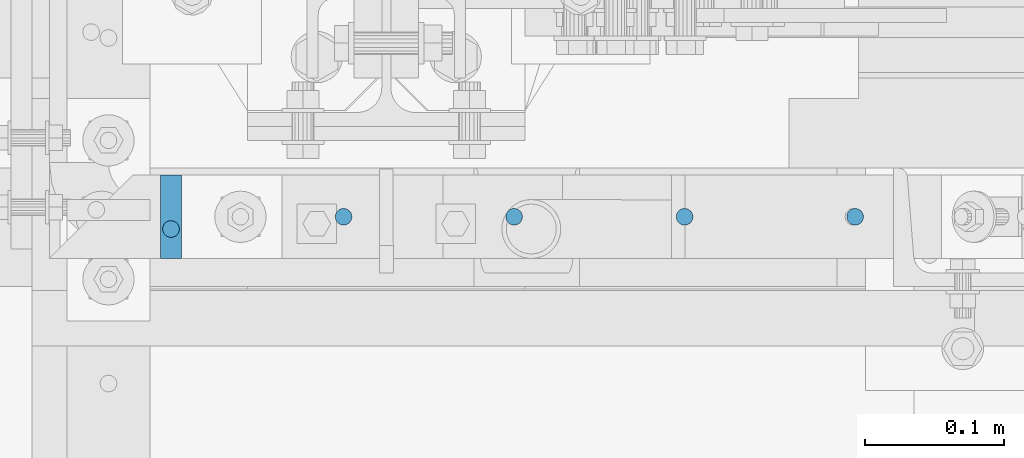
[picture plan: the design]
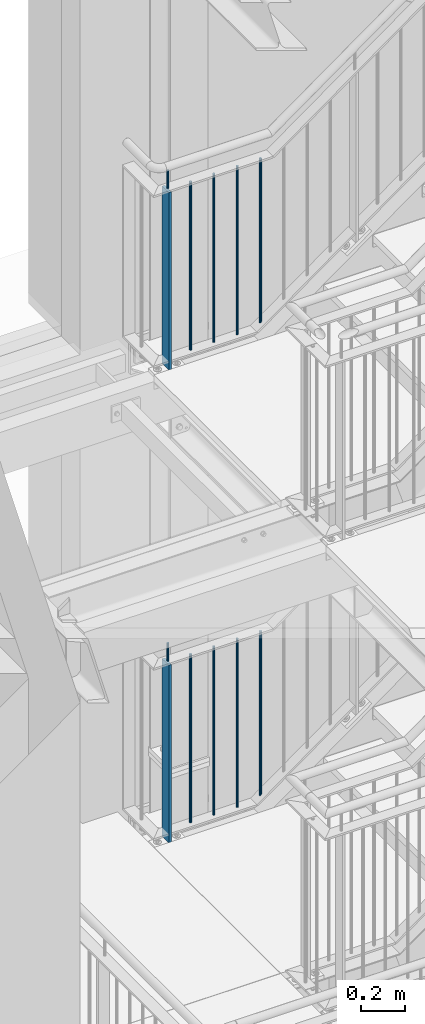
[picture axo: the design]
# One storey, part 70 of 825: 12 columns.
"""IFC2X3 building model written with IfcOpenShell, lengths in millimetres."""

from ifc_helpers import new_model, entity, si_unit, converted_unit, frame, origin, origin_with_axes, origin_2d, place, context, project, spatial, rectangle, circle, extrude, clip, halfspace, material, element, save


model = new_model("IFC2X3")

# Units and contexts
model_context = context("Model", 3, precision=1e-09, world=origin_with_axes())
ifc_project = project(units=[si_unit("LENGTHUNIT", "METRE", prefix="MILLI"), si_unit("AREAUNIT", "SQUARE_METRE"), si_unit("VOLUMEUNIT", "CUBIC_METRE"), converted_unit("PLANEANGLEUNIT", "DEGREE", entity("IfcPlaneAngleMeasure", 0.01745329), si_unit("PLANEANGLEUNIT", "RADIAN"), dimensions=[0, 0, 0, 0, 0, 0, 0])], contexts=[model_context])

# Site, building, storey
site_placement = place(None, origin_with_axes())
site = spatial("IfcSite", under=ifc_project, at=site_placement, CompositionType="ELEMENT")
building_placement = place(site_placement, origin_with_axes())
building = spatial("IfcBuilding", under=site, at=building_placement, Name="1", CompositionType="ELEMENT")
storey_placement = place(building_placement, origin_with_axes())
storey = spatial("IfcBuildingStorey", under=building, at=storey_placement, Name="Default Storey", CompositionType="ELEMENT", Elevation=0.0)

# Columns
ifc_material = material(Name="S235JR")
column_1_placement = place(None, frame((4701.713402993, 7356.736971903, 8359.723292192), z_axis=(0.0, 0.0, 1.0), x_axis=(1.0, 0.0, 0.0)))
element("IfcColumn", 1, at=column_1_placement, inside=storey, material=ifc_material, Name="Railing_Post_Landing#0", ObjectType="Railing_Post_Landing#0", context=model_context, shape_type="Clipping", body=[
    clip(clip(extrude(rectangle(XDim=15.0, YDim=60.0, at=origin_2d()), origin(), (0.0, 0.0, -1.0), 1070.646584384), halfspace(frame((-4701.713402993, -7356.736971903, -1019.722292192), z_axis=(0.0, 0.0, 1.0), x_axis=(1.0, 0.0, 0.0)), True)), halfspace(frame((-4701.713402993, -7356.736971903, -30.924292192), z_axis=(0.0, 0.0, -1.0), x_axis=(-1.0, 0.0, 0.0)), True)),
])
column_2_placement = place(None, frame((4825.963402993, 7356.736971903, 8342.285281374), z_axis=(0.0, 0.0, 1.0), x_axis=(1.0, 0.0, 0.0)))
element("IfcColumn", 2, at=column_2_placement, inside=storey, material=ifc_material, Name="Railing_Picket_Landing#0", ObjectType="Railing_Picket_Landing#0", context=model_context, shape_type="Clipping", body=[
    clip(clip(extrude(circle(Radius=6.0, at=origin_2d()), origin(), (0.0, 0.0, -1.0), 965.770562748), halfspace(frame((-4825.963402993, -7356.736971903, -13.486281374), z_axis=(0.0, 0.0, -1.0), x_axis=(-1.0, 0.0, 0.0)), True)), halfspace(frame((-4825.963402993, -7356.736971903, -952.284281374), z_axis=(0.0, 0.0, 1.0), x_axis=(1.0, 0.0, 0.0)), True)),
])
column_3_placement = place(None, frame((4948.713426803, 7356.736971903, 8342.285281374), z_axis=(0.0, 0.0, 1.0), x_axis=(1.0, 0.0, 0.0)))
element("IfcColumn", 3, at=column_3_placement, inside=storey, material=ifc_material, Name="Railing_Picket_Landing#1", ObjectType="Railing_Picket_Landing#1", context=model_context, shape_type="Clipping", body=[
    clip(clip(extrude(circle(Radius=6.0, at=origin_2d()), origin(), (0.0, 0.0, -1.0), 965.770562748), halfspace(frame((-4948.713426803, -7356.736971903, -13.486281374), z_axis=(0.0, 0.0, -1.0), x_axis=(-1.0, 0.0, 0.0)), True)), halfspace(frame((-4948.713426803, -7356.736971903, -952.284281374), z_axis=(0.0, 0.0, 1.0), x_axis=(1.0, 0.0, 0.0)), True)),
])
column_4_placement = place(None, frame((5071.463450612, 7356.736971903, 8342.285281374), z_axis=(0.0, 0.0, 1.0), x_axis=(1.0, 0.0, 0.0)))
element("IfcColumn", 4, at=column_4_placement, inside=storey, material=ifc_material, Name="Railing_Picket_Landing#2", ObjectType="Railing_Picket_Landing#2", context=model_context, shape_type="Clipping", body=[
    clip(extrude(circle(Radius=6.0, at=origin_2d()), origin(), (0.0, 0.0, -1.0), 952.285281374), halfspace(frame((-5071.463450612, -7356.736971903, -13.486281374), z_axis=(0.0, 0.0, -1.0), x_axis=(-1.0, 0.0, 0.0)), True)),
])
column_5_placement = place(None, frame((5194.213474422, 7356.736971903, 8328.8), z_axis=(0.0, 0.0, 1.0), x_axis=(1.0, 0.0, 0.0)))
element("IfcColumn", 5, at=column_5_placement, inside=storey, material=ifc_material, Name="Railing_Picket_Stair#3", ObjectType="Railing_Picket_Stair#3", context=model_context, shape_type="Clipping", body=[
    clip(extrude(circle(Radius=6.0, at=origin_2d()), origin(), (0.0, 0.0, -1.0), 923.619455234), halfspace(frame((-6931.981901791, -7356.736971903, -5925.503238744), z_axis=(-0.585945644, 0.0, 0.810350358), x_axis=(0.0, -1.0, 0.0)), True)),
])
column_6_placement = place(None, frame((4701.713402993, 7347.936971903, 8447.285281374), z_axis=(0.0, 0.0, 1.0), x_axis=(0.0, -1.0, 0.0)))
element("IfcColumn", 6, at=column_6_placement, inside=storey, material=ifc_material, Name="Bar#0", ObjectType="Bar#0", context=model_context, shape_type="Clipping", body=[
    clip(clip(extrude(circle(Radius=6.0, at=origin_2d()), origin(), (0.0, 0.0, -1.0), 116.970562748), halfspace(frame((7347.936971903, -4701.713402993, -8.486281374), z_axis=(0.0, 0.0, -1.0), x_axis=(0.0, -1.0, 0.0)), True)), halfspace(frame((7347.936971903, -4701.713402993, -108.484281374), z_axis=(0.0, 0.0, 1.0), x_axis=(0.0, 1.0, 0.0)), True)),
])
column_7_placement = place(None, frame((4701.713402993, 7356.736971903, 10991.723292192), z_axis=(0.0, 0.0, 1.0), x_axis=(1.0, 0.0, 0.0)))
element("IfcColumn", 7, at=column_7_placement, inside=storey, material=ifc_material, Name="Railing_Post_Landing#0", ObjectType="Railing_Post_Landing#0", context=model_context, shape_type="Clipping", body=[
    clip(clip(extrude(rectangle(XDim=15.0, YDim=60.0, at=origin_2d()), origin(), (0.0, 0.0, -1.0), 1070.646584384), halfspace(frame((-4701.713402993, -7356.736971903, -1019.722292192), z_axis=(0.0, 0.0, 1.0), x_axis=(1.0, 0.0, 0.0)), True)), halfspace(frame((-4701.713402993, -7356.736971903, -30.924292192), z_axis=(0.0, 0.0, -1.0), x_axis=(-1.0, 0.0, 0.0)), True)),
])
column_8_placement = place(None, frame((4825.963402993, 7356.736971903, 10974.285281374), z_axis=(0.0, 0.0, 1.0), x_axis=(1.0, 0.0, 0.0)))
element("IfcColumn", 8, at=column_8_placement, inside=storey, material=ifc_material, Name="Railing_Picket_Landing#0", ObjectType="Railing_Picket_Landing#0", context=model_context, shape_type="Clipping", body=[
    clip(clip(extrude(circle(Radius=6.0, at=origin_2d()), origin(), (0.0, 0.0, -1.0), 965.770562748), halfspace(frame((-4825.963402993, -7356.736971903, -13.486281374), z_axis=(0.0, 0.0, -1.0), x_axis=(-1.0, 0.0, 0.0)), True)), halfspace(frame((-4825.963402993, -7356.736971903, -952.284281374), z_axis=(0.0, 0.0, 1.0), x_axis=(1.0, 0.0, 0.0)), True)),
])
column_9_placement = place(None, frame((4948.713426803, 7356.736971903, 10974.285281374), z_axis=(0.0, 0.0, 1.0), x_axis=(1.0, 0.0, 0.0)))
element("IfcColumn", 9, at=column_9_placement, inside=storey, material=ifc_material, Name="Railing_Picket_Landing#1", ObjectType="Railing_Picket_Landing#1", context=model_context, shape_type="Clipping", body=[
    clip(clip(extrude(circle(Radius=6.0, at=origin_2d()), origin(), (0.0, 0.0, -1.0), 965.770562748), halfspace(frame((-4948.713426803, -7356.736971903, -13.486281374), z_axis=(0.0, 0.0, -1.0), x_axis=(-1.0, 0.0, 0.0)), True)), halfspace(frame((-4948.713426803, -7356.736971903, -952.284281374), z_axis=(0.0, 0.0, 1.0), x_axis=(1.0, 0.0, 0.0)), True)),
])
column_10_placement = place(None, frame((5071.463450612, 7356.736971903, 10974.285281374), z_axis=(0.0, 0.0, 1.0), x_axis=(1.0, 0.0, 0.0)))
element("IfcColumn", 10, at=column_10_placement, inside=storey, material=ifc_material, Name="Railing_Picket_Landing#2", ObjectType="Railing_Picket_Landing#2", context=model_context, shape_type="Clipping", body=[
    clip(clip(extrude(circle(Radius=6.0, at=origin_2d()), origin(), (0.0, 0.0, -1.0), 965.770562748), halfspace(frame((-5071.463450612, -7356.736971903, -13.486281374), z_axis=(0.0, 0.0, -1.0), x_axis=(-1.0, 0.0, 0.0)), True)), halfspace(frame((-5071.463450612, -7356.736971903, -952.284281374), z_axis=(0.0, 0.0, 1.0), x_axis=(1.0, 0.0, 0.0)), True)),
])
column_11_placement = place(None, frame((5194.213474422, 7356.736971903, 10960.8), z_axis=(0.0, 0.0, 1.0), x_axis=(1.0, 0.0, 0.0)))
element("IfcColumn", 11, at=column_11_placement, inside=storey, material=ifc_material, Name="Railing_Picket_Stair#3", ObjectType="Railing_Picket_Stair#3", context=model_context, shape_type="Clipping", body=[
    clip(extrude(circle(Radius=6.0, at=origin_2d()), origin(), (0.0, 0.0, -1.0), 923.610556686), halfspace(frame((-8183.31391831, -7356.736971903, -6819.069656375), z_axis=(-0.585213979, 0.0, 0.810878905), x_axis=(0.0, -1.0, 0.0)), True)),
])
column_12_placement = place(None, frame((4701.713402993, 7347.936971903, 11079.285281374), z_axis=(0.0, 0.0, 1.0), x_axis=(0.0, -1.0, 0.0)))
element("IfcColumn", 12, at=column_12_placement, inside=storey, material=ifc_material, Name="Bar#0", ObjectType="Bar#0", context=model_context, shape_type="Clipping", body=[
    clip(clip(extrude(circle(Radius=6.0, at=origin_2d()), origin(), (0.0, 0.0, -1.0), 116.970562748), halfspace(frame((7347.936971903, -4701.713402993, -8.486281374), z_axis=(0.0, 0.0, -1.0), x_axis=(0.0, -1.0, 0.0)), True)), halfspace(frame((7347.936971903, -4701.713402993, -108.484281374), z_axis=(0.0, 0.0, 1.0), x_axis=(0.0, 1.0, 0.0)), True)),
])

save(model, "model.ifc")
